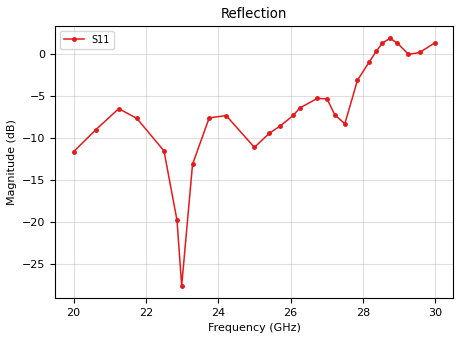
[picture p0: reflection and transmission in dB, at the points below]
! freq	mag(S11)	phase(S11)
!ADF5904 RF3
#  Hz  S  MA  R 50
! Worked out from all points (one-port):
!   1001 points, 20 GHz to 30 GHz, reference 50 ohm
!   lowest |S11| = -27.5 dB at 22.99 GHz (marker M1), VSWR 1.09, Z = 46.4 - j1.87 ohm
!   |S11| at or under -10 dB: start of sweep to 20.51 GHz; 22.29 GHz to 23.45 GHz (1.158 GHz wide, 5.06 % of centre); 24.67 GHz to 25.3 GHz (627.1 MHz wide, 2.51 % of centre)
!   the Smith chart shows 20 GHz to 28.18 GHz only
!   S11 on the Smith chart (normalised r, x): 20 GHz: 1.03, +0.55; 22.86 GHz: 0.86, +0.13; 26.08 GHz: 0.58, -0.60; 27.22 GHz: 1.98, +0.94; 28.18 GHz: 0.06, +0.35
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2e10  0.262 71.9
2.061e10  0.3529 21.5
2.125e10  0.4722 39.4
2.175e10  0.4135 72.0
2.25e10  0.2652 102.1
2.286e10  0.1028 133.2
2.299e10  0.04196 -151.4
2.329e10  0.2206 -51.6
2.375e10  0.4161 -11.7
2.422e10  0.4296 24.3
2.5e10  0.2782 105.7
2.541e10  0.3369 142.9
2.572e10  0.3736 -176.2
2.608e10  0.4316 -104.3
2.625e10  0.4758 -74.1
2.674e10  0.5438 -14.8
2.701e10  0.5396 7.7
2.722e10  0.435 26.2
2.75e10  0.3839 94.5
2.785e10  0.697 125.6
2.818e10  0.8979 140.9
2.837e10  1.035 158.7
2.854e10  1.16 -177.1
2.875e10  1.235 -139.5
2.895e10  1.159 -103.3
2.926e10  0.9923 -58.8
2.957e10  1.018 -30.4
3e10  1.167 -1.7
